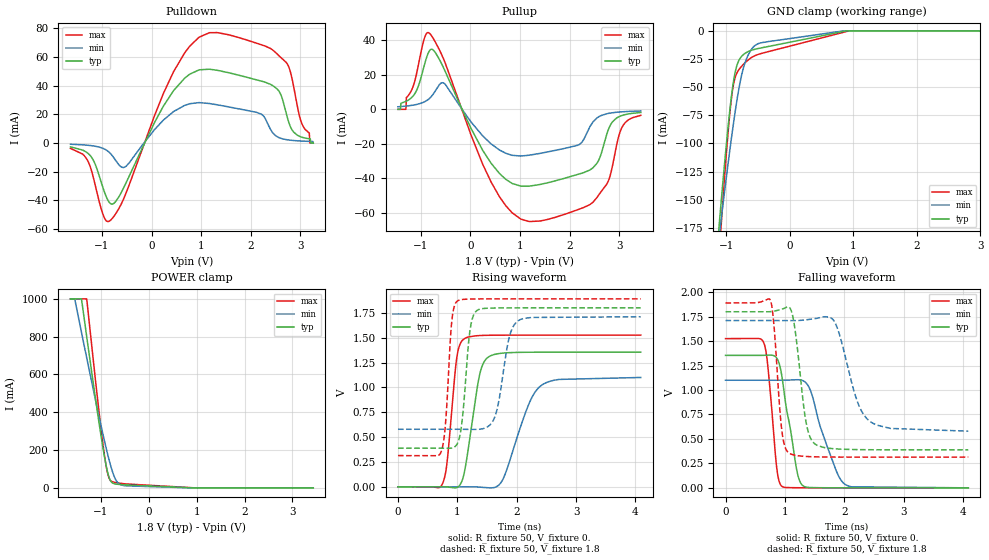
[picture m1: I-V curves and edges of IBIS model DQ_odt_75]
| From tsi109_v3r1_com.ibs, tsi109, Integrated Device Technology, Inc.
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|   MODEL DQ_odt_75
[Model]   DQ_odt_75
Model_type  I/O
Polarity   Non-Inverting
Enable   Active-Low
|   typ   min   max
|C_comp_off 3.363p 3.4p 3.318p
|C_comp_on 3.698p 3.621p 3.948p
C_comp 3.53p 3.51p 3.633p
Cref  =   20pF
Vmeas =   0.9v
Vinl  =   0.650v
Vinh  =   1.150v
[Model Spec]
[Temperature Range]   25   125   0
[Voltage Range] 1.8 1.71 1.89
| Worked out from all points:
|   slope of the pulldown table from 0 to 0.27 V, typ, clamps not added: 15.5 ohm
|   slope of the pullup table from 0 to 0.27 V, typ, clamps not added: 18.7 ohm
|   rising waveform, R_fixture 50, V_fixture 0.: 20-80 % time 205ps typ, 380ps min, 137ps max; typ from 0 V to 1.35 V
|   rising waveform, R_fixture 50, V_fixture 1.8: 20-80 % time 121ps typ, 188ps min, 93.3ps max; typ from 0.389 V to 1.8 V
|   falling waveform, R_fixture 50, V_fixture 0.: 20-80 % time 211ps typ, 348ps min, 129ps max; typ from 1.35 V to 0 V
|   falling waveform, R_fixture 50, V_fixture 1.8: 20-80 % time 164ps typ, 316ps min, 113ps max; typ from 1.8 V to 0.389 V
[Pulldown]
-1.636V   -2.749mA   -869.2uA   -3.779mA
-1.22V    -9.523mA   -1.848mA   -18.31mA
-982.8mV  -30.99mA   -3.738mA   -49.62mA
-834.2mV  -42.14mA   -7.191mA   -54.06mA
-512.5mV  -27.58mA   -16.15mA   -34.67mA
442.9mV   36.55mA    21.94mA    49.75mA
1.166V    51.46mA    27.52mA    76.92mA
2.215V    43.12mA    20.1mA     68.47mA
2.438V    40.09mA    7.284mA    64.95mA
2.715V    20.68mA    2.355mA    56.15mA
3.017V    4.187mA    1.352mA    14.69mA
3.26V     0A         0A         0A
[Pullup]
-1.46V    0A         1.493mA    0A
-1.301V   4.568mA    1.878mA    0A
-1.088V   10.76mA    2.811mA    20.24mA
-826mV    33.9mA     6.297mA    44.13mA
-524mV    23.04mA    14.98mA    28.03mA
416.5mV   -31.17mA   -19.99mA   -42.04mA
1.189V    -44.52mA   -26.57mA   -65.03mA
2.204V    -37.38mA   -20.25mA   -57.75mA
2.476V    -33.78mA   -7.136mA   -53.72mA
2.872V    -7.045mA   -1.945mA   -31.9mA
3.06V     -3.537mA   -1.423mA   -10.29mA
3.436V    -1.832mA   -944.9uA   -3.489mA
[GND Clamp]
-1.636V   -544.5mA   -441.7mA   -680.8mA
-1.123V   -182.1mA   -189mA     -211.5mA
-1.098V   -165.6mA   -177.3mA   -190.4mA
-1.074V   -149.3mA   -165.6mA   -169.7mA
-959.1mV  -80.05mA   -113.8mA   -84.1mA
-914.3mV  -57.55mA   -94.64mA   -59.42mA
-874.4mV  -41.91mA   -78.49mA   -45.25mA
-814.7mV  -28.31mA   -56.62mA   -35.88mA
-720.1mV  -20.78mA   -31.57mA   -29.35mA
-530.9mV  -16.15mA   -12.45mA   -21.7mA
935.2mV   0A         0A         0A
3.26V     0A         0A         0A
[Power Clamp]
-1.636V   1A         1A         1A
-1.546V   1A         997.4mA    1A
-1.407V   998.4mA    824mA      1A
-1.297V   800.3mA    688.1mA    998.9mA
-1.083V   418.1mA    428.5mA    498.6mA
-928.2mV  168.8mA    251.1mA    176.9mA
-848.4mV  71mA       166.8mA    66.16mA
-763.6mV  26.63mA    89.57mA    32.79mA
-648.9mV  18.72mA    27.94mA    26.18mA
-474.4mV  15.54mA    10.87mA    20.84mA
954.8mV   0A         0A         0A
3.436V    0A         0A         0A
[Ramp]
dV/dt_r .812/205.375p .66/380.602p .915/136.332p
dV/dt_f .847/163.938p .679/315.888p .946/112.754p
[Rising Waveform]
R_fixture = 50
V_fixture = 0.
0s        0V         0V         0V
750ps     198.9uV    -789.9nV   31.79mV
820ps     -1.136mV   10.99uV    212.1mV
990ps     -8.18mV    142.4uV    1.294V
1.12ns    152.2mV    239.9uV    1.49V
1.37ns    1.113V     -2.911mV   1.521V
1.53ns    1.308V     -9.701mV   1.524V
1.77ns    1.345V     78.26mV    1.525V
2.41ns    1.354V     1.017V     1.525V
4.09ns    1.354V     1.1V       1.525V
[Rising Waveform]
R_fixture = 50
V_fixture = 1.8
V_fixture_min = 1.71
V_fixture_max = 1.89
0s        388.5mV    578.6mV    314.1mV
730ps     388.1mV    578.7mV    357.9mV
800ps     387.6mV    578.7mV    630.1mV
900ps     389.8mV    578.7mV    1.627V
1ns       434.4mV    578.6mV    1.868V
1.21ns    1.561V     577.2mV    1.888V
1.33ns    1.773V     577.6mV    1.889V
1.63ns    1.798V     701.1mV    1.89V
2.03ns    1.8V       1.672V     1.89V
4.09ns    1.8V       1.71V      1.89V
[Falling Waveform]
R_fixture = 50
V_fixture = 0.
0s        1.354V     1.1V       1.525V
640ps     1.355V     1.1V       1.49V
720ps     1.356V     1.1V       1.203V
860ps     1.329V     1.1V       217.9mV
960ps     1.099V     1.1V       11.48mV
1.2ns     183.3mV    1.105V     1.23mV
1.31ns    19.37mV    1.094V     714.3uV
1.86ns    480.7uV    183.1mV    48.69uV
2.02ns    258.4uV    33.45mV    22.5uV
4.09ns    0V         23.14uV    0V
[Falling Waveform]
R_fixture = 50
V_fixture = 1.8
V_fixture_min = 1.71
V_fixture_max = 1.89
0s        1.8V       1.71V      1.89V
760ps     1.801V     1.71V      1.916V
940ps     1.824V     1.71V      632.1mV
1.08ns    1.84V      1.71V      351.9mV
1.17ns    1.623V     1.71V      333.6mV
1.36ns    662.2mV    1.718V     320.8mV
1.51ns    446.5mV    1.73V      317.2mV
1.84ns    399.2mV    1.694V     314.7mV
2.42ns    389.6mV    685.4mV    314.2mV
4.09ns    388.5mV    579.6mV    314.1mV
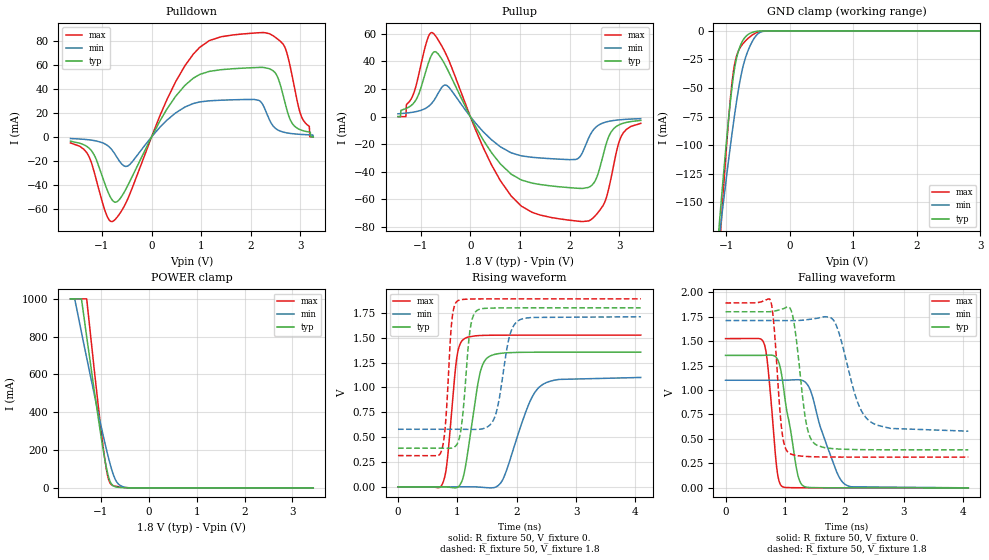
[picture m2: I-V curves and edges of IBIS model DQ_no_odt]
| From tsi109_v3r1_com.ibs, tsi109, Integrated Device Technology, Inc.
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|   MODEL DQ_no_odt
[Model]   DQ_no_odt
Model_type  I/O
Polarity   Non-Inverting
Enable   Active-Low
|   typ   min   max
|C_comp_off 3.919p 3.972p 3.845p
|C_comp_on 3.698p 3.62p 3.948p
C_comp 3.809p 3.796p 3.896p
Cref  =   20pF
Vmeas =   0.9v
Vinl  =   0.650v
Vinh  =   1.150v
[Model Spec]
[Temperature Range]   25   125   0
[Voltage Range] 1.8 1.71 1.89
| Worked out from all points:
|   slope of the pulldown table from 0 to 0.27 V, typ, clamps not added: 13.2 ohm
|   slope of the pullup table from 0 to 0.27 V, typ, clamps not added: 15.4 ohm
|   GND clamp passes 1 mA (typ) near -0.57 V on its own axis
|   POWER clamp passes 1 mA (typ) near -0.54 V on its own axis
|   rising waveform, R_fixture 50, V_fixture 0.: 20-80 % time 205ps typ, 380ps min, 137ps max; typ from 0 V to 1.35 V
|   rising waveform, R_fixture 50, V_fixture 1.8: 20-80 % time 121ps typ, 188ps min, 93.3ps max; typ from 0.389 V to 1.8 V
|   falling waveform, R_fixture 50, V_fixture 0.: 20-80 % time 211ps typ, 348ps min, 129ps max; typ from 1.35 V to 0 V
|   falling waveform, R_fixture 50, V_fixture 1.8: 20-80 % time 164ps typ, 316ps min, 113ps max; typ from 1.8 V to 0.389 V
[Pulldown]
-1.636V   -3.649mA   -1.42mA    -5.055mA
-1.275V   -8.922mA   -2.436mA   -15.46mA
-913.5mV  -42.38mA   -6.562mA   -64.55mA
-784.8mV  -53.15mA   -11.67mA   -70.44mA
-482.8mV  -40.74mA   -24.38mA   -51.92mA
304.3mV   22.85mA    13.69mA    30.62mA
838.9mV   48.83mA    27.75mA    68.81mA
2.235V    57.86mA    27.32mA    86.89mA
2.507V    52.5mA     6.75mA     82.54mA
2.68V     30.08mA    3.705mA    75.24mA
3.002V    5.838mA    2.051mA    19.08mA
3.26V     0A         0A         0A
[Pullup]
-1.46V    0A         2.056mA    0A
-1.301V   5.791mA    2.542mA    0A
-756.7mV  46.08mA    10.65mA    60.6mA
-464.6mV  34.39mA    22.34mA    43.2mA
263.1mV   -17.14mA   -11.08mA   -22.74mA
822.5mV   -41.66mA   -26.22mA   -57.48mA
2.263V    -52.03mA   -25.85mA   -76.01mA
2.496V    -47.78mA   -8.921mA   -72.68mA
2.674V    -28.4mA    -4.593mA   -64.52mA
2.892V    -8.672mA   -2.791mA   -34.76mA
3.085V    -4.751mA   -2.084mA   -11.69mA
3.436V    -2.732mA   -1.461mA   -4.887mA
[GND Clamp]
-1.636V   -543.7mA   -441.2mA   -679.6mA
-1.113V   -173.3mA   -183.3mA   -199.6mA
-1.089V   -157.2mA   -171.9mA   -178.9mA
-1.065V   -141.4mA   -160.5mA   -158.5mA
-948.9mV  -70.59mA   -107.9mA   -69.79mA
-881.1mV  -38.31mA   -79.34mA   -34.33mA
-837.5mV  -24.54mA   -62.52mA   -22.45mA
-784.3mV  -14.23mA   -44.56mA   -15.18mA
-639mV    -2.666mA   -15.21mA   -5.883mA
-532.5mV  -543.1uA   -4.536mA   -1.841mA
-416.4mV  -69.24uA   -425.6uA   -218.8uA
3.26V     0A         0A         0A
[Power Clamp]
-1.636V   1A         1A         1A
-1.549V   1A         1A         1A
-1.411V   1A         828.4mA    1A
-1.298V   800.8mA    688.6mA    1A
-1.047V   355mA      385.4mA    415.3mA
-944.5mV  189.4mA    267.9mA    200.5mA
-857.4mV  74.25mA    174.4mA    62.22mA
-821.5mV  42.19mA    138.8mA    31.99mA
-780.5mV  20.7mA     101.5mA    16.68mA
-657.5mV  3.818mA    26.99mA    6.851mA
-462.8mV  270uA      1.332mA    1.058mA
3.436V    0A         0A         0A
[Ramp]
dV/dt_r .812/205.375p .66/380.602p .915/136.332p
dV/dt_f .847/163.938p .679/315.888p .946/112.754p
[Rising Waveform]
R_fixture = 50
V_fixture = 0.
0s        0V         0V         0V
750ps     198.9uV    -789.9nV   31.79mV
820ps     -1.136mV   10.99uV    212.1mV
990ps     -8.18mV    142.4uV    1.294V
1.12ns    152.2mV    239.9uV    1.49V
1.37ns    1.113V     -2.911mV   1.521V
1.53ns    1.308V     -9.701mV   1.524V
1.77ns    1.345V     78.26mV    1.525V
2.41ns    1.354V     1.017V     1.525V
4.09ns    1.354V     1.1V       1.525V
[Rising Waveform]
R_fixture = 50
V_fixture = 1.8
V_fixture_min = 1.71
V_fixture_max = 1.89
0s        388.5mV    578.6mV    314.1mV
730ps     388.1mV    578.7mV    357.9mV
800ps     387.6mV    578.7mV    630.1mV
900ps     389.8mV    578.7mV    1.627V
1ns       434.4mV    578.6mV    1.868V
1.21ns    1.561V     577.2mV    1.888V
1.33ns    1.773V     577.6mV    1.889V
1.63ns    1.798V     701.1mV    1.89V
2.03ns    1.8V       1.672V     1.89V
4.09ns    1.8V       1.71V      1.89V
[Falling Waveform]
R_fixture = 50
V_fixture = 0.
0s        1.354V     1.1V       1.525V
640ps     1.355V     1.1V       1.49V
720ps     1.356V     1.1V       1.203V
860ps     1.329V     1.1V       217.9mV
960ps     1.099V     1.1V       11.48mV
1.2ns     183.3mV    1.105V     1.23mV
1.31ns    19.37mV    1.094V     714.3uV
1.86ns    480.7uV    183.1mV    48.69uV
2.02ns    258.4uV    33.45mV    22.5uV
4.09ns    0V         23.14uV    0V
[Falling Waveform]
R_fixture = 50
V_fixture = 1.8
V_fixture_min = 1.71
V_fixture_max = 1.89
0s        1.8V       1.71V      1.89V
760ps     1.801V     1.71V      1.916V
940ps     1.824V     1.71V      632.1mV
1.08ns    1.84V      1.71V      351.9mV
1.17ns    1.623V     1.71V      333.6mV
1.36ns    662.2mV    1.718V     320.8mV
1.51ns    446.5mV    1.73V      317.2mV
1.84ns    399.2mV    1.694V     314.7mV
2.42ns    389.6mV    685.4mV    314.2mV
4.09ns    388.5mV    579.6mV    314.1mV
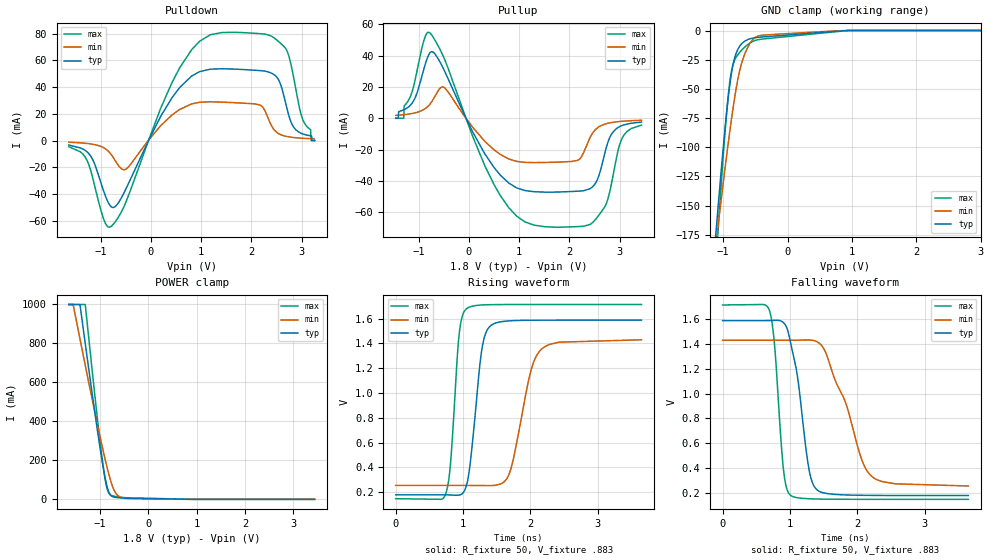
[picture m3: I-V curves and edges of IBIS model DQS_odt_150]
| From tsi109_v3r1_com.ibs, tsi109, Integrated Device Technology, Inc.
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|   MODEL DQS_odt_150
[Model]   DQS_odt_150
Model_type  I/O
Polarity   Non-Inverting
Enable   Active-Low
|   typ   min   max
|C_comp_off 3.705p 3.757p 3.636p
|C_comp_on 3.3p 3.205p 3.514p
C_comp 3.503p 3.481p 3.575p
Cref  =   20pF
Vmeas =   0.9v
Vinl  =   0.650v
Vinh  =   1.150v
[Model Spec]
[Temperature Range]   25   125   0
[Voltage Range] 1.8 1.71 1.89
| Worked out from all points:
|   slope of the pulldown table from 0 to 0.27 V, typ, clamps not added: 14 ohm
|   slope of the pullup table from 0 to 0.27 V, typ, clamps not added: 16.6 ohm
|   rising waveform, R_fixture 50, V_fixture .883: 20-80 % time 155ps typ, 260ps min, 111ps max; typ from 0.179 V to 1.59 V
|   falling waveform, R_fixture 50, V_fixture .883: 20-80 % time 211ps typ, 436ps min, 121ps max; typ from 1.59 V to 0.179 V
[Pulldown]
-1.636V   -3.323mA   -1.212mA   -4.599mA
-1.21V    -11.07mA   -2.446mA   -21.09mA
-933.3mV  -38.78mA   -5.524mA   -59.65mA
-784.8mV  -49.73mA   -10.81mA   -63.97mA
-502.6mV  -36.5mA    -21.48mA   -46.35mA
571.6mV   39.71mA    23.3mA     54.46mA
1.423V    53.79mA    28.81mA    80.93mA
2.176V    52.4mA     26.59mA    80.07mA
2.403V    50.45mA    10.95mA    78.12mA
2.68V     28.57mA    3.287mA    69.15mA
3.002V    5.316mA    1.795mA    18.12mA
3.26V     0A         0A         0A
[Pullup]
-1.46V    0A         1.84mA     0A
-1.301V   5.351mA    2.288mA    0A
-1.078V   12.65mA    3.443mA    23.66mA
-791.3mV  41.1mA     8.484mA    54.75mA
-494.3mV  30.7mA     19.67mA    38.23mA
624.5mV   -36.24mA   -23.04mA   -49.29mA
1.674V    -47.11mA   -28.05mA   -69.43mA
2.204V    -46.44mA   -26.01mA   -69.03mA
2.496V    -42.58mA   -8.056mA   -65.51mA
2.857V    -9.27mA    -2.618mA   -38.81mA
3.06V     -4.507mA   -1.881mA   -12.14mA
3.436V    -2.406mA   -1.258mA   -4.39mA
[GND Clamp]
-1.636V   -544mA     -441.4mA   -680mA
-1.124V   -180.9mA   -188.5mA   -209.5mA
-1.099V   -164.3mA   -176.7mA   -188.1mA
-1.074V   -147.9mA   -165mA     -167.2mA
-964.3mV  -80.44mA   -115.2mA   -82.44mA
-884.7mV  -41.57mA   -81.42mA   -39.48mA
-795.1mV  -19.11mA   -48.76mA   -22.6mA
-660.7mV  -9.028mA   -19.65mA   -14.03mA
-541.2mV  -6.508mA   -7.863mA   -9.392mA
-411.8mV  -5.625mA   -4.125mA   -7.467mA
937.8mV   0A         0A         0A
3.26V     0A         0A         0A
[Power Clamp]
-1.636V   1A         1A         1A
-1.546V   1A         997.3mA    1A
-1.407V   998.2mA    823.6mA    1A
-1.297V   799.4mA    687.6mA    998.5mA
-1.063V   382.4mA    404.2mA    451.3mA
-928mV    166.1mA    250.1mA    171.6mA
-883.1mV  105.4mA    201.6mA    98.24mA
-843.2mV  61.99mA    160.6mA    52.13mA
-758.4mV  18mA       84.13mA    19.98mA
-648.7mV  9.117mA    25.5mA     13.77mA
-474.1mV  6.076mA    5.11mA     8.511mA
3.436V    0A         0A         0A
[Ramp]
dV/dt_r .845/154.678p .705/260.261p .939/110.93p
dV/dt_f .845/210.589p .705/436.081p .939/121.27p
[Rising Waveform]
R_fixture = 50
V_fixture = .883
V_fixture_min = .842
V_fixture_max = .931
0s        179.2mV    255.2mV    148.5mV
740ps     179.2mV    255.2mV    184.6mV
810ps     178.4mV    255.2mV    406.7mV
950ps     178.3mV    255.3mV    1.509V
1.05ns    252.2mV    255.2mV    1.679V
1.27ns    1.317V     254.5mV    1.709V
1.41ns    1.542V     253.8mV    1.712V
1.69ns    1.582V     354.6mV    1.713V
2.15ns    1.587V     1.345V     1.714V
3.65ns    1.588V     1.429V     1.714V
[Falling Waveform]
R_fixture = 50
V_fixture = .883
V_fixture_min = .842
V_fixture_max = .931
0s        1.588V     1.429V     1.714V
700ps     1.588V     1.429V     1.664V
780ps     1.59V      1.429V     1.342V
900ps     1.574V     1.429V     410.3mV
1.02ns    1.385V     1.43V      176.4mV
1.11ns    1.147V     1.43V      161.6mV
1.29ns    371.6mV    1.431V     153mV
1.41ns    221.4mV    1.415V     150.8mV
2.21ns    180.2mV    336.1mV    148.5mV
3.65ns    179.2mV    256.1mV    148.5mV
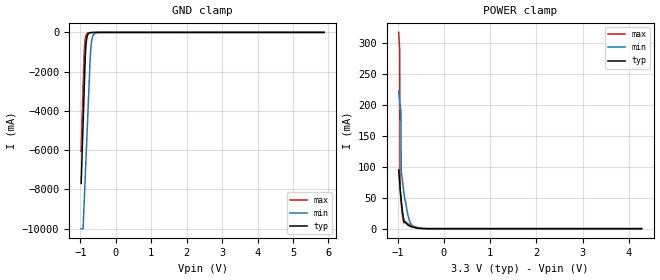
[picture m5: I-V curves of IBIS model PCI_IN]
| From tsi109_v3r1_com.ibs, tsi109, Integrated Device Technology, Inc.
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|   MODEL PCI_IN
[Model]   PCI_IN
Model_type  Input
C_comp 4.536p 4.267p 4.874p
Polarity   Non-Inverting
Enable   Active-High
Vinl =   0.80V
Vinh =   2.00V
[Model Spec]
[Temperature Range]   25.0   125.0   0.0
[Voltage Range] 3.3 3. 3.6
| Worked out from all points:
|   GND clamp passes 1 mA (typ) near -0.58 V on its own axis
|   POWER clamp passes 1 mA (typ) near -0.59 V on its own axis
[GND Clamp]
-976.9mV  -7.694A    -10A       -6.059A
-923.3mV  -4.682A    -10A       -2.776A
-891.1mV  -2.879A    -8.618A    -995.9mA
-863.2mV  -1.353A    -7.407A    -348.1mA
-850.3mV  -868.3mA   -6.848A    -216.4mA
-837.4mV  -553.5mA   -6.29A     -136.9mA
-794.5mV  -126.9mA   -4.431A    -37.38mA
-727.9mV  -18.49mA   -1.562A    -12.3mA
-708.6mV  -11.57mA   -935.5mA   -10.19mA
-670mV    -5.111mA   -330.6mA   -7.318mA
-603.5mV  -1.592mA   -60.06mA   -3.898mA
5.879V    0A         0A         0A
[Power Clamp]
-976.9mV  94.83mA    222.1mA    316.9mA
-955.2mV  74.24mA    206.7mA    290.2mA
-949.7mV  69.36mA    202.9mA    93.51mA
-944.3mV  64.58mA    199.1mA    61.59mA
-928mV    51.03mA    188mA      45.37mA
-922.5mV  46.77mA    94.48mA    40.53mA
-895.3mV  28.34mA    76.94mA    20.86mA
-868.1mV  15.36mA    60.48mA    9.595mA
-840.9mV  10.95mA    45.93mA    9.334mA
-737.6mV  4.25mA     11.82mA    6.323mA
-558.1mV  630.6uA    1.342mA    1.718mA
4.277V    0A         0A         0A
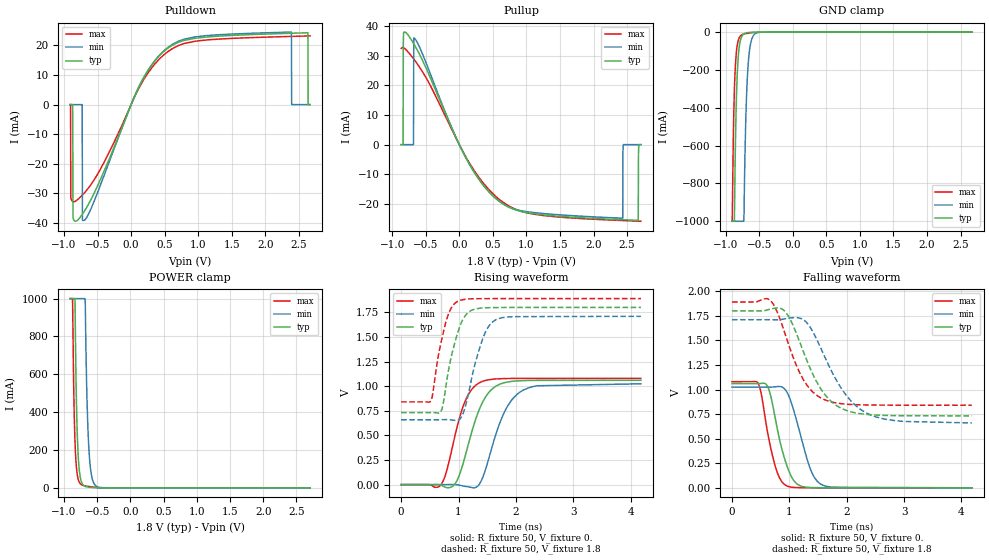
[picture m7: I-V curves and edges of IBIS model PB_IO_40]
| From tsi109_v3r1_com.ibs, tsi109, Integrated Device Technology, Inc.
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|   MODEL PB_IO_40
[Model]   PB_IO_40
Model_type  I/O
Polarity   Non-Inverting
Enable   Active-High
|   typ   min   max
|C_comp_off 3.714p 3.514p 3.979p
|C_comp_on 4.164p 3.795p 4.513p
C_comp 3.939p 3.654p 4.246p
Vinl  =   0.300v
Vinh  =   1.500v
Vmeas =   0.9000V
Cref  =   1.0pF
Rref  =   50.0000
Vref  =   0.0V
[Model Spec]
[Temperature Range]   25   125   0
[Voltage Range] 1.8 1.71 1.89
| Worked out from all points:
|   slope of the pulldown table from 0 to 0.27 V, typ, clamps not added: 22.1 ohm
|   slope of the pullup table from 0 to 0.27 V, typ, clamps not added: 24.6 ohm
|   GND clamp passes 1 mA (typ) near -0.59 V on its own axis
|   POWER clamp passes 1 mA (typ) near -0.54 V on its own axis
|   rising waveform, R_fixture 50, V_fixture 0.: 20-80 % time 351ps typ, 382ps min, 301ps max; typ from 0 V to 1.06 V
|   rising waveform, R_fixture 50, V_fixture 1.8: 20-80 % time 243ps typ, 281ps min, 212ps max; typ from 0.732 V to 1.8 V
|   falling waveform, R_fixture 50, V_fixture 0.: 20-80 % time 258ps typ, 298ps min, 219ps max; typ from 1.06 V to 0 V
|   falling waveform, R_fixture 50, V_fixture 1.8: 20-80 % time 512ps typ, 613ps min, 441ps max; typ from 1.8 V to 0.732 V
[Pulldown]
-906mV    0A         0A         0A
-898.8mV  0A         0A         -31.56mA
-826.6mV  -39.45mA   0A         -32.61mA
-729mV    -37.15mA   0A         -30.65mA
-725.4mV  -37.03mA   -39.06mA   -30.56mA
-696.5mV  -36.04mA   -39.11mA   -29.85mA
611.1mV   20.04mA    20.31mA    18.87mA
2.388V    24.12mA    24.53mA    23.05mA
2.392V    24.12mA    0A         23.05mA
2.634V    24.29mA    0A         23.2mA
2.638V    0A         0A         23.21mA
2.667V    0A         0A         23.23mA
[Pullup]
-866.6mV  0A         0A         32.53mA
-837.7mV  0A         0A         32.8mA
-834.1mV  34.47mA    0A         32.78mA
-816mV    38.07mA    0A         32.53mA
-682.3mV  34.23mA    0A         29.05mA
-675.1mV  33.95mA    36.08mA    28.83mA
740.9mV   -21.2mA    -21.1mA    -20.77mA
2.435V    -25.4mA    -24.88mA   -25.67mA
2.442V    -25.41mA   0A         -25.68mA
2.666V    -25.61mA   0A         -25.88mA
2.674V    0A         0A         -25.88mA
2.706V    0A         0A         -25.91mA
[GND Clamp]
-906mV    -1A        -1A        -1A
-902.1mV  -1A        -1A        -991.7mA
-886.2mV  -1A        -1A        -554.9mA
-870.4mV  -1A        -1A        -309.1mA
-858.5mV  -676.1mA   -1A        -200.9mA
-826.9mV  -218.6mA   -1A        -68.27mA
-771.4mV  -32.66mA   -1A        -17.55mA
-727.9mV  -9.631mA   -986.9mA   -10.26mA
-700.2mV  -5.362mA   -461.4mA   -8.035mA
-664.5mV  -2.969mA   -169.3mA   -5.932mA
-561.6mV  -598.3uA   -9.09mA    -1.877mA
2.667V    0A         0A         0A
[Power Clamp]
-906mV    1A         1A         1A
-872.1mV  1A         1A         1A
-856.7mV  1A         1A         564.2mA
-835.1mV  996.9mA    1A         240.6mA
-819.7mV  566mA      1A         134.1mA
-801.2mV  284.1mA    1A         70.16mA
-748.7mV  43.94mA    1A         19.45mA
-683.9mV  7.977mA    1A         10.28mA
-653.1mV  4.793mA    446.3mA    8.344mA
-628.4mV  3.454mA    219.8mA    7.029mA
-520.4mV  746.2uA    9.952mA    2.56mA
2.706V    0A         0A         0A
[Ramp]
dV/dt_r .636/350.688p .615/382.229p .648/300.4p
dV/dt_f .641/511.996p .631/613.561p .63/441.011p
[Rising Waveform]
R_fixture = 50
V_fixture = 0.
0s        0V         0V         0V
670ps     -1.16mV    -44.07uV   -15.48mV
770ps     -26.04mV   63.45uV    95.18mV
910ps     -11.48mV   804uV      424.1mV
1.14ns    340.9mV    -19.6mV    879mV
1.39ns    801.1mV    30.65mV    1.042V
1.55ns    950.6mV    311.4mV    1.067V
1.77ns    1.031V     698.4mV    1.077V
2.09ns    1.056V     947.3mV    1.079V
4.18ns    1.06V      1.024V     1.08V
[Rising Waveform]
R_fixture = 50
V_fixture = 1.8
V_fixture_min = 1.71
V_fixture_max = 1.89
0s        731.7mV    659.2mV    840.2mV
510ps     732mV      659.2mV    844.1mV
550ps     732.7mV    659.2mV    921.3mV
690ps     737.8mV    659.4mV    1.428V
830ps     1.175V     659.7mV    1.742V
1ns       1.569V     655.4mV    1.866V
1.11ns    1.71V      775.2mV    1.883V
1.43ns    1.795V     1.495V     1.89V
1.65ns    1.799V     1.675V     1.89V
4.18ns    1.8V       1.71V      1.89V
[Falling Waveform]
R_fixture = 50
V_fixture = 0.
0s        1.06V      1.024V     1.08V
440ps     1.06V      1.024V     1.075V
500ps     1.062V     1.024V     984.2mV
600ps     1.05V      1.024V     632.5mV
780ps     630.3mV    1.029V     172.1mV
960ps     220.6mV    971.1mV    18.87mV
1.12ns    46.82mV    698.4mV    2.919mV
1.36ns    3.689mV    201.6mV    683uV
1.56ns    1.25mV     33.8mV     261.3uV
4.18ns    0V         8.143uV    0V
[Falling Waveform]
R_fixture = 50
V_fixture = 1.8
V_fixture_min = 1.71
V_fixture_max = 1.89
0s        1.8V       1.71V      1.89V
640ps     1.813V     1.71V      1.917V
760ps     1.828V     1.709V     1.825V
900ps     1.807V     1.717V     1.611V
1.04ns    1.684V     1.729V     1.37V
1.28ns    1.333V     1.694V     1.068V
1.6ns     963.7mV    1.354V     899.7mV
1.98ns    790.4mV    950.2mV    851.6mV
2.4ns     744.2mV    745.9mV    842.5mV
4.18ns    731.7mV    660.1mV    840.2mV
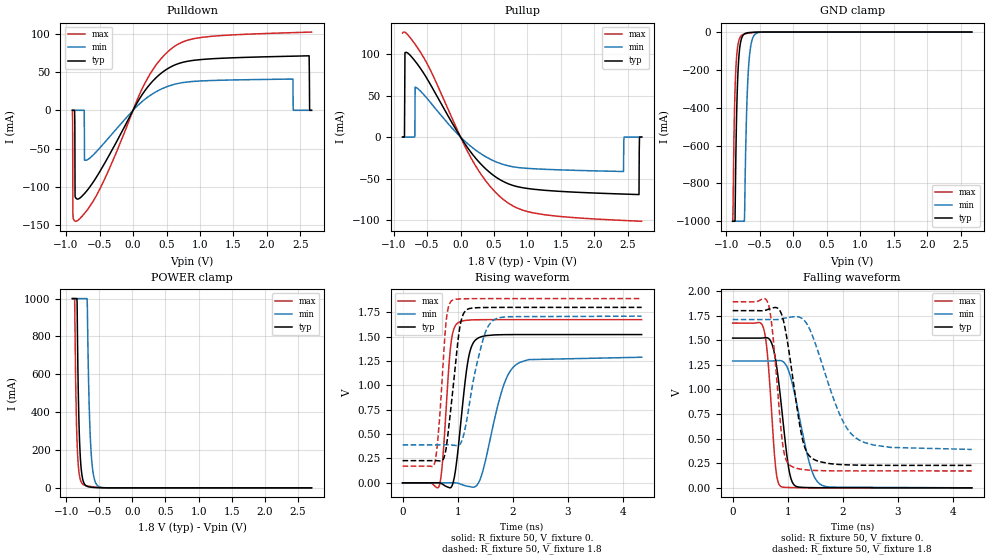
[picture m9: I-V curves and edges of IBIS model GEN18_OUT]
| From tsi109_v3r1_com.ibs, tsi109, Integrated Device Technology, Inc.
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[Model]   GEN18_OUT
Model_type  Output
Polarity   Non-Inverting
Enable   Active-High
|   typ   min   max
|C_comp_off 3.714p 3.514p 3.979p
|C_comp_on 4.671p 4.383p 5.086p
C_comp 4.192p 3.948p 4.532p
Vinl  =   0.300v
Vinh  =   1.500v
Vmeas =   0.9000V
Cref  =   1.0pF
Rref  =   50.0000
Vref  =   0.0V
[Model Spec]
[Temperature Range]   25   125   0
[Voltage Range] 1.8 1.71 1.89
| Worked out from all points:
|   slope of the pulldown table from 0 to 0.27 V, typ, clamps not added: 7.56 ohm
|   slope of the pullup table from 0 to 0.27 V, typ, clamps not added: 9.12 ohm
|   GND clamp passes 1 mA (typ) near -0.59 V on its own axis
|   POWER clamp passes 1 mA (typ) near -0.54 V on its own axis
|   rising waveform, R_fixture 50, V_fixture 0.: 20-80 % time 178ps typ, 338ps min, 120ps max; typ from 0 V to 1.52 V
|   rising waveform, R_fixture 50, V_fixture 1.8: 20-80 % time 179ps typ, 281ps min, 122ps max; typ from 0.228 V to 1.8 V
|   falling waveform, R_fixture 50, V_fixture 0.: 20-80 % time 187ps typ, 296ps min, 125ps max; typ from 1.52 V to 0 V
|   falling waveform, R_fixture 50, V_fixture 1.8: 20-80 % time 255ps typ, 510ps min, 162ps max; typ from 1.8 V to 0.228 V
[Pulldown]
-905.5mV  0A         0A         0A
-901.8mV  0A         0A         -15.16mA
-898.2mV  0A         0A         -134.4mA
-873mV    0A         0A         -144.2mA
-865.7mV  -112.5mA   0A         -144.6mA
-847.7mV  -115.1mA   0A         -144.7mA
-728.5mV  -109mA     0A         -134.9mA
-696mV    -105.6mA   -65mA      -131.3mA
640.2mV   59.77mA    34.43mA    84.61mA
2.63V     71.14mA    0A         102mA
2.637V    0A         0A         102.1mA
2.666V    0A         0A         102.1mA
[Pullup]
-866.2mV  0A         0A         125.4mA
-837.3mV  0A         0A         126.5mA
-830.1mV  101.7mA    0A         126.3mA
-801.2mV  101.8mA    0A         124.4mA
-685.7mV  92.24mA    0A         112.7mA
-674.8mV  91.13mA    60.07mA    111.5mA
672.2mV   -54.92mA   -33.85mA   -77.31mA
2.435V    -68.76mA   -41.53mA   -100.6mA
2.442V    -68.78mA   0A         -100.6mA
2.666V    -69.35mA   0A         -101.4mA
2.673V    0A         0A         -101.4mA
2.705V    0A         0A         -101.6mA
[GND Clamp]
-905.5mV  -1A        -1A        -1A
-901.5mV  -1A        -1A        -974.7mA
-885.7mV  -1A        -1A        -543.1mA
-869.8mV  -997.8mA   -1A        -302.8mA
-858mV    -662.6mA   -1A        -196.7mA
-826.3mV  -214.2mA   -1A        -66.87mA
-770.9mV  -32.02mA   -1A        -17.32mA
-727.3mV  -9.494mA   -973.7mA   -10.21mA
-699.6mV  -5.303mA   -454.7mA   -8.003mA
-664mV    -2.948mA   -166.9mA   -5.905mA
-565.1mV  -634.9uA   -10.08mA   -1.971mA
2.666V    0A         0A         0A
[Power Clamp]
-905.5mV  1A         1A         1A
-871.5mV  1A         1A         999.8mA
-856.1mV  1A         1A         551.7mA
-837.6mV  1A         1A         265.1mA
-816mV    494.2mA    1A         117.5mA
-800.6mV  278.3mA    1A         69.01mA
-742mV    35.25mA    1A         17.64mA
-683.4mV  7.9mA      1A         10.24mA
-652.6mV  4.758mA    440.2mA    8.318mA
-615.6mV  2.935mA    152.1mA    6.395mA
-520mV    740.6uA    9.847mA    2.544mA
2.705V    0A         0A         0A
[Ramp]
dV/dt_r .913/177.771p .773/338.311p 1.004/120.281p
dV/dt_f .943/254.559p .793/510.536p 1.031/161.904p
[Rising Waveform]
R_fixture = 50
V_fixture = 0.
0s        0V         0V         0V
670ps     -91.55uV   -48.8uV    -23.8mV
730ps     -14.39mV   -186.7uV   243.6mV
870ps     -49.24mV   857.7uV    1.386V
1.01ns    355.9mV    -4.331mV   1.644V
1.19ns    1.258V     -35.6mV    1.669V
1.37ns    1.485V     -8.159mV   1.673V
1.81ns    1.52V      956.8mV    1.674V
2.05ns    1.521V     1.208V     1.674V
4.34ns    1.521V     1.288V     1.674V
[Rising Waveform]
R_fixture = 50
V_fixture = 1.8
V_fixture_min = 1.71
V_fixture_max = 1.89
0s        227.8mV    389.2mV    171.6mV
580ps     228.6mV    389.2mV    196.2mV
650ps     226.7mV    389.2mV    504.6mV
790ps     349.2mV    390.3mV    1.652V
890ps     832.8mV    388.3mV    1.868V
1.02ns    1.521V     387.4mV    1.886V
1.1ns     1.727V     473.1mV    1.888V
1.43ns    1.798V     1.406V     1.89V
1.65ns    1.8V       1.668V     1.89V
4.34ns    1.8V       1.71V      1.89V
[Falling Waveform]
R_fixture = 50
V_fixture = 0.
0s        1.521V     1.289V     1.674V
560ps     1.523V     1.289V     1.623V
640ps     1.522V     1.289V     1.302V
780ps     1.299V     1.291V     204.9mV
870ps     906.3mV    1.292V     15.36mV
1ns       260.5mV    1.212V     3.797mV
1.08ns    60.62mV    1.067V     2.372mV
1.4ns     2.408mV    238.9mV    473.4uV
1.6ns     1.072mV    32.47mV    183.1uV
4.34ns    0V         13.39uV    0V
[Falling Waveform]
R_fixture = 50
V_fixture = 1.8
V_fixture_min = 1.71
V_fixture_max = 1.89
0s        1.8V       1.71V      1.89V
640ps     1.813V     1.71V      1.879V
720ps     1.827V     1.709V     1.605V
900ps     1.744V     1.718V     476.5mV
1.04ns    1.319V     1.733V     229.1mV
1.26ns    511.6mV    1.721V     187.4mV
1.46ns    293.4mV    1.528V     177.4mV
1.92ns    238mV      776.1mV    172.3mV
2.24ns    231.1mV    505.4mV    171.8mV
4.34ns    227.8mV    390.2mV    171.6mV
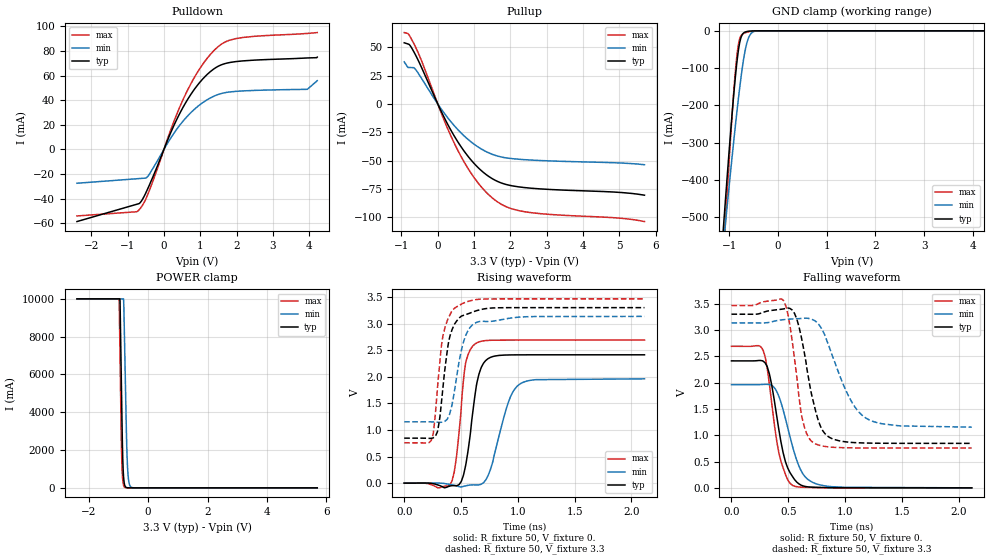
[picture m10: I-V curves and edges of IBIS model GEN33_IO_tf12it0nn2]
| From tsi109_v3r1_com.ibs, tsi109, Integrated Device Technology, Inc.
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|   MODEL GEN33_IO_tf12it0nn2
[Model]   GEN33_IO_tf12it0nn2
Model_type  I/O
C_comp 1.247p 1.176p 1.342p
Polarity   Non-Inverting
Enable   Active-High
|   typ   min   max
Vinl   =   0.800v
Vinh   =   2.000v
Vmeas  =   1.65V
[Model Spec]
[Temperature Range]   25   125   0
[Voltage Range] 3.3 3.135 3.465
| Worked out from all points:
|   slope of the pulldown table from 0 to 0.495 V, typ, clamps not added: 15.2 ohm
|   slope of the pullup table from 0 to 0.495 V, typ, clamps not added: 16.3 ohm
|   GND clamp passes 1 mA (typ) near -0.60 V on its own axis
|   POWER clamp passes 1 mA (typ) near -0.62 V on its own axis
|   rising waveform, R_fixture 50, V_fixture 0.: 20-80 % time 92.1ps typ, 147ps min, 70.9ps max; typ from 0 V to 2.41 V
|   rising waveform, R_fixture 50, V_fixture 3.3: 20-80 % time 90.2ps typ, 107ps min, 84.6ps max; typ from 0.845 V to 3.3 V
|   falling waveform, R_fixture 50, V_fixture 0.: 20-80 % time 121ps typ, 155ps min, 109ps max; typ from 2.41 V to 0 V
|   falling waveform, R_fixture 50, V_fixture 3.3: 20-80 % time 137ps typ, 233ps min, 99.2ps max; typ from 3.3 V to 0.845 V
[Pulldown]
-2.396V   -58.62mA   -27.49mA   -54.06mA
-756mV    -44.63mA   -23.86mA   -50.65mA
-662.3mV  -43.5mA    -23.65mA   -48.32mA
-434.7mV  -31.22mA   -21.51mA   -35.84mA
187.8mV   13.66mA    9.223mA    15.92mA
555.9mV   35.75mA    23.97mA    42.3mA
1.071V    57.29mA    38.05mA    69.29mA
1.52V     67.92mA    44.88mA    84.11mA
1.821V    70.64mA    46.71mA    88.84mA
2.169V    71.91mA    47.53mA    90.92mA
3.95V     74.3mA     48.8mA     94.22mA
4.224V    74.99mA    55.83mA    94.92mA
[Pullup]
-924.1mV  53.85mA    37.04mA    62.83mA
-796.9mV  52.53mA    32.1mA     61.01mA
-663mV    46.15mA    31.85mA    53.38mA
-576mV    40.84mA    28.84mA    47.65mA
133.5mV   -9.109mA   -6.162mA   -11.06mA
588.7mV   -35.17mA   -23.83mA   -43.1mA
1.037V    -53.69mA   -36.34mA   -66.5mA
1.526V    -66.31mA   -44.68mA   -83.43mA
1.874V    -70.9mA    -47.5mA    -90.41mA
2.383V    -73.68mA   -49.1mA    -94.93mA
5.067V    -78.08mA   -52.1mA    -100.8mA
5.696V    -80.41mA   -53.59mA   -103.6mA
[GND Clamp]
-2.396V   -2.986A    -2.401A    -3.708A
-1.121V   -533.1mA   -577.5mA   -612.5mA
-1.081V   -461.9mA   -523.7mA   -523.1mA
-937.9mV  -219.3mA   -335.6mA   -221.8mA
-890.1mV  -147.5mA   -275.8mA   -136.1mA
-850.3mV  -94.66mA   -227.6mA   -77.18mA
-786.5mV  -33.49mA   -155.3mA   -22.37mA
-746.7mV  -14.38mA   -114.5mA   -11.27mA
-690.9mV  -4.535mA   -65.97mA   -6.169mA
-587.4mV  -835.4uA   -14.53mA   -2.198mA
-443.9mV  -45.4uA    -524.9uA   -178.2uA
4.224V    0A         0A         0A
[Power Clamp]
-2.396V   10A        10A        10A
-976.4mV  10A        10A        10A
-952.8mV  10A        10A        7.72A
-944.9mV  9.88A      10A        6.899A
-905.5mV  6.038A     10A        2.817A
-881.8mV  3.741A     10A        1.213A
-858.1mV  1.8A       10A        482.2mA
-826.6mV  591.4mA    10A        135.5mA
-787.2mV  135.4mA    7.258A     30.19mA
-700.4mV  6.514mA    1.351A     4.157mA
-574.2mV  501.8uA    37.92mA    1.305mA
5.696V    0A         0A         0A
[Ramp]
dV/dt_r 1.448/92.129p 1.177/146.688p 1.614/70.788p
dV/dt_f 1.473/136.637p 1.19/233.06p 1.625/99.24p
[Rising Waveform]
R_fixture = 50
V_fixture = 0.
0s        514.3nV    829.9nV    0V
315ps     -47.89mV   -434.8uV   -89.09mV
420ps     -48.36mV   -33.69mV   35.24mV
460ps     -48.53mV   -53.68mV   490.4mV
540ps     324.4mV    -51.57mV   2.25V
640ps     1.887V     -34.35mV   2.639V
740ps     2.343V     150.7mV    2.684V
915ps     2.41V      1.509V     2.689V
1.015ns   2.412V     1.858V     2.689V
2.115ns   2.413V     1.961V     2.689V
[Rising Waveform]
R_fixture = 50
V_fixture = 3.3
V_fixture_min = 3.135
V_fixture_max = 3.465
0s        845.1mV    1.152V     757.2mV
235ps     841.3mV    1.152V     794.1mV
260ps     857.8mV    1.15V      998.3mV
290ps     953.2mV    1.146V     1.714V
345ps     1.882V     1.152V     2.807V
400ps     2.742V     1.299V     3.152V
465ps     3.058V     2.044V     3.32V
540ps     3.168V     2.769V     3.402V
655ps     3.253V     3.035V     3.456V
2.115ns   3.3V       3.135V     3.465V
[Falling Waveform]
R_fixture = 50
V_fixture = 0.
0s        2.413V     1.961V     2.69V
280ps     2.405V     1.965V     2.608V
335ps     2.157V     1.962V     1.951V
380ps     1.623V     1.895V     1.168V
420ps     1.072V     1.722V     639.2mV
475ps     498.9mV    1.318V     256.4mV
540ps     206.9mV    770.5mV    44.37mV
645ps     29.04mV    219.5mV    10.6mV
790ps     7.195mV    50.93mV    2.931mV
2.115ns   27.36uV    31.28uV    31.61uV
[Falling Waveform]
R_fixture = 50
V_fixture = 3.3
V_fixture_min = 3.135
V_fixture_max = 3.465
0s        3.3V       3.135V     3.465V
460ps     3.401V     3.196V     3.555V
515ps     3.409V     3.206V     3.079V
575ps     3.209V     3.214V     2.116V
620ps     2.81V      3.219V     1.343V
720ps     1.644V     3.191V     859.4mV
845ps     985.4mV    2.766V     780.4mV
1.025ns   869.6mV    1.77V      761.2mV
1.185ns   851.7mV    1.324V     758.1mV
2.115ns   845.2mV    1.153V     757.3mV
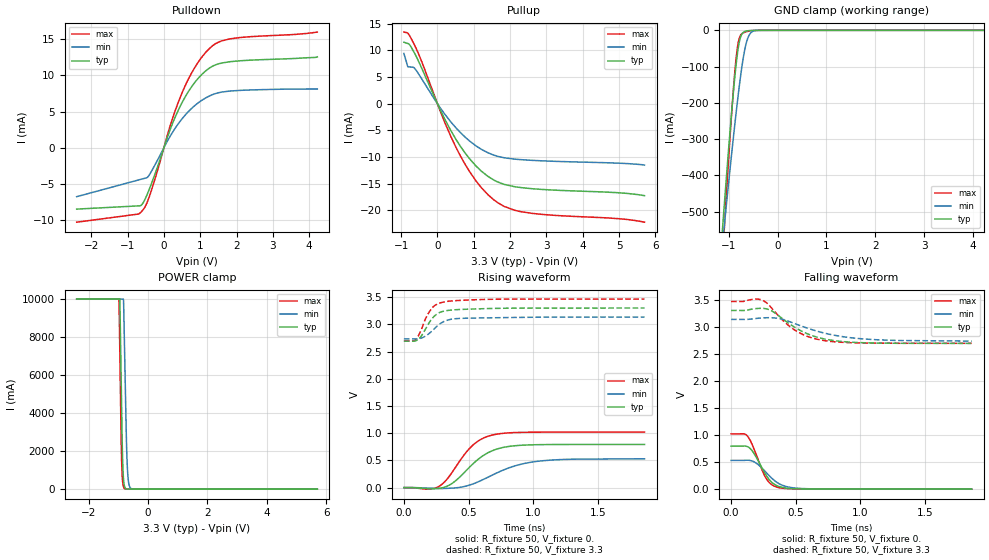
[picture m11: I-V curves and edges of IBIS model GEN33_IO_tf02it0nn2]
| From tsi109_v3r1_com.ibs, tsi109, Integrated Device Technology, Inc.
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|   MODEL GEN33_IO_tf02it0nn2
[Model]   GEN33_IO_tf02it0nn2
Model_type  I/O
C_comp 1.184p 1.112p 1.271p
Polarity   Non-Inverting
Enable   Active-High
|   typ   min   max
Vinl   =   0.800v
Vinh   =   2.000v
Vmeas  =   1.65V
[Model Spec]
[Temperature Range]   25   125   0
[Voltage Range] 3.3 3.135 3.465
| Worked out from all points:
|   slope of the pulldown table from 0 to 0.495 V, typ, clamps not added: 80 ohm
|   slope of the pullup table from 0 to 0.495 V, typ, clamps not added: 76 ohm
|   GND clamp passes 1 mA (typ) near -0.60 V on its own axis
|   POWER clamp passes 1 mA (typ) near -0.62 V on its own axis
|   rising waveform, R_fixture 50, V_fixture 0.: 20-80 % time 230ps typ, 323ps min, 202ps max; typ from 0 V to 0.794 V
|   rising waveform, R_fixture 50, V_fixture 3.3: 20-80 % time 107ps typ, 127ps min, 97.8ps max; typ from 2.69 V to 3.3 V
|   falling waveform, R_fixture 50, V_fixture 0.: 20-80 % time 118ps typ, 144ps min, 106ps max; typ from 0.794 V to 0 V
|   falling waveform, R_fixture 50, V_fixture 3.3: 20-80 % time 275ps typ, 373ps min, 237ps max; typ from 3.3 V to 2.69 V
[Pulldown]
-2.4V     -8.474mA   -6.758mA   -10.28mA
-705.4mV  -8.028mA   -4.456mA   -9.161mA
-564.7mV  -7.544mA   -4.265mA   -8.519mA
-397.3mV  -5.675mA   -3.724mA   -6.694mA
-176.3mV  -2.658mA   -1.719mA   -3.165mA
192.1mV   2.763mA    1.758mA    3.33mA
480.2mV   6.041mA    3.873mA    7.342mA
882mV     9.223mA    5.958mA    11.34mA
1.13V     10.53mA    6.827mA    13.06mA
1.331V    11.25mA    7.327mA    14.06mA
1.82V     11.9mA     7.841mA    15.05mA
4.224V    12.56mA    8.123mA    15.99mA
[Pullup]
-924.4mV  11.54mA    9.439mA    13.44mA
-817.2mV  11.3mA     6.948mA    13.24mA
-663.2mV  9.892mA    6.827mA    11.44mA
-576.1mV  8.753mA    6.18mA     10.21mA
194.2mV   -2.791mA   -1.888mA   -3.393mA
636.3mV   -8.028mA   -5.438mA   -9.847mA
1.065V    -11.7mA    -7.919mA   -14.51mA
1.554V    -14.32mA   -9.642mA   -18.03mA
2.123V    -15.55mA   -10.38mA   -19.97mA
2.612V    -15.94mA   -10.62mA   -20.56mA
4.977V    -16.69mA   -11.14mA   -21.54mA
5.7V      -17.24mA   -11.51mA   -22.21mA
[GND Clamp]
-2.4V     -2.994A    -2.407A    -3.719A
-1.124V   -538mA     -581.2mA   -618.7mA
-1.092V   -480.9mA   -538mA     -546.9mA
-1.068V   -438.5mA   -505.9mA   -493.7mA
-932.5mV  -210.8mA   -328.7mA   -211.5mA
-852.8mV  -97.7mA    -230.6mA   -80.32mA
-788.9mV  -35.11mA   -157.9mA   -23.45mA
-741.1mV  -12.71mA   -109.1mA   -10.44mA
-685.3mV  -4.075mA   -61.77mA   -5.86mA
-581.6mV  -759.7uA   -13.1mA    -2.046mA
-438mV    -39.16uA   -446.5uA   -155.4uA
4.224V    0A         0A         0A
[Power Clamp]
-2.4V     10A        10A        10A
-979mV    10A        10A        10A
-947.4mV  10A        10A        7.164A
-908mV    6.281A     10A        3.058A
-884.3mV  3.983A     10A        1.332A
-852.7mV  1.498A     10A        387.8mA
-821.1mV  483.4mA    9.885A     109mA
-789.5mV  148.4mA    7.442A     32.83mA
-702.7mV  6.966mA    1.436A     4.27mA
-655.3mV  2.051mA    388.6mA    2.727mA
-576.4mV  519.3uA    40.48mA    1.336mA
5.7V      0A         0A         0A
[Ramp]
dV/dt_r .476/230.063p .318/323.059p .612/201.762p
dV/dt_f .365/274.969p .241/374.442p .463/237.433p
[Rising Waveform]
R_fixture = 50
V_fixture = 0.
0s        0V         0V         0V
185ps     -20.24mV   -8.288mV   -28.27mV
280ps     -9.948mV   -16.97mV   35.78mV
375ps     81.29mV    -8.553mV   288.1mV
520ps     405.4mV    56.43mV    750.9mV
600ps     567.4mV    134.5mV    892.9mV
680ps     674.4mV    226.6mV    964.2mV
865ps     771.2mV    404.2mV    1.012V
1.065ns   790.1mV    492.3mV    1.019V
1.86ns    793.7mV    530.4mV    1.02V
[Rising Waveform]
R_fixture = 50
V_fixture = 3.3
V_fixture_min = 3.135
V_fixture_max = 3.465
0s        2.691V     2.733V     2.693V
90ps      2.696V     2.731V     2.719V
130ps     2.771V     2.745V     2.879V
165ps     2.904V     2.782V     3.093V
220ps     3.112V     2.884V     3.306V
275ps     3.217V     3.003V     3.389V
320ps     3.248V     3.063V     3.416V
385ps     3.266V     3.101V     3.433V
505ps     3.28V      3.114V     3.448V
1.86ns    3.3V       3.135V     3.465V
[Falling Waveform]
R_fixture = 50
V_fixture = 0.
0s        793.7mV    530.7mV    1.02V
125ps     786.7mV    534mV      983.8mV
175ps     667.7mV    508.2mV    753.1mV
235ps     410.5mV    397.6mV    379.8mV
275ps     241.2mV    298.2mV    183.1mV
315ps     125.8mV    201.9mV    81.41mV
360ps     58.96mV    116.5mV    33.3mV
450ps     14.43mV    36.11mV    8.764mV
575ps     4.444mV    9.419mV    3.204mV
1.86ns    2.98uV     32.28uV    1.306uV
[Falling Waveform]
R_fixture = 50
V_fixture = 3.3
V_fixture_min = 3.135
V_fixture_max = 3.465
0s        3.3V       3.135V     3.465V
235ps     3.339V     3.161V     3.494V
310ps     3.298V     3.166V     3.353V
395ps     3.152V     3.139V     3.13V
480ps     3.008V     3.069V     2.958V
575ps     2.884V     2.985V     2.835V
695ps     2.788V     2.898V     2.754V
850ps     2.728V     2.821V     2.713V
1.05ns    2.702V     2.769V     2.698V
1.86ns    2.692V     2.734V     2.693V
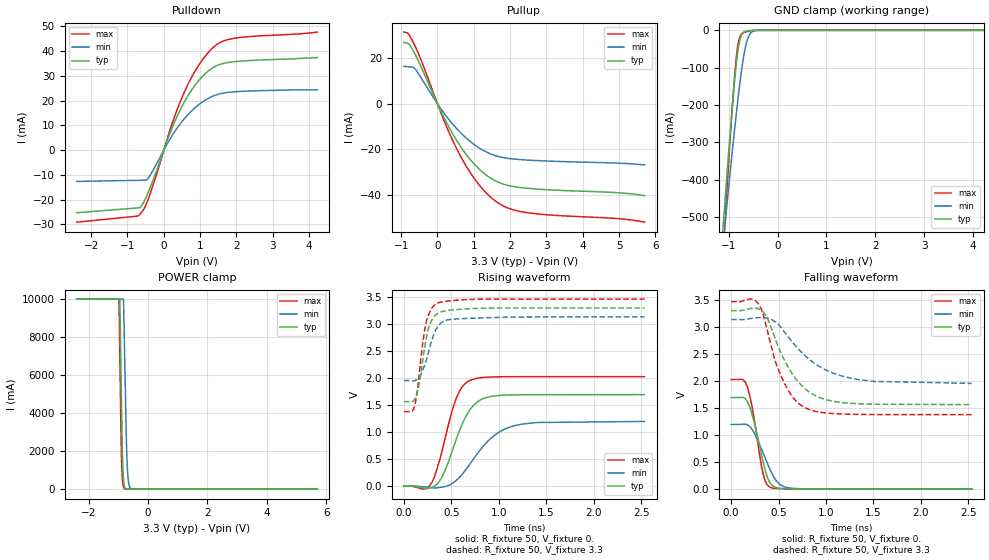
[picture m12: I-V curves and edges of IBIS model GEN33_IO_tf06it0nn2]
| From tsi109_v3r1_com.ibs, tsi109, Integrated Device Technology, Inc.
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|   MODEL GEN33_IO_tf06it0nn2
[Model]   GEN33_IO_tf06it0nn2
Model_type  I/O
C_comp 1.25p 1.174p 1.348p
Polarity   Non-Inverting
Enable   Active-High
|   typ   min   max
Vinl   =   0.800v
Vinh   =   2.000v
Vmeas  =   1.65V
[Model Spec]
[Temperature Range]   25   125   0
[Voltage Range] 3.3 3.135 3.465
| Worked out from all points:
|   slope of the pulldown table from 0 to 0.495 V, typ, clamps not added: 28.2 ohm
|   slope of the pullup table from 0 to 0.495 V, typ, clamps not added: 32.6 ohm
|   GND clamp passes 1 mA (typ) near -0.60 V on its own axis
|   POWER clamp passes 1 mA (typ) near -0.62 V on its own axis
|   rising waveform, R_fixture 50, V_fixture 0.: 20-80 % time 229ps typ, 345ps min, 188ps max; typ from 0 V to 1.69 V
|   rising waveform, R_fixture 50, V_fixture 3.3: 20-80 % time 103ps typ, 130ps min, 93.2ps max; typ from 1.56 V to 3.3 V
|   falling waveform, R_fixture 50, V_fixture 0.: 20-80 % time 136ps typ, 179ps min, 113ps max; typ from 1.69 V to 0 V
|   falling waveform, R_fixture 50, V_fixture 3.3: 20-80 % time 317ps typ, 447ps min, 247ps max; typ from 3.3 V to 1.56 V
[Pulldown]
-2.399V   -25.3mA    -12.63mA   -29.11mA
-731.1mV  -23.35mA   -12.19mA   -26.68mA
-610.6mV  -22.46mA   -12.16mA   -25.09mA
-423.1mV  -16.79mA   -11.23mA   -19.56mA
213.1mV   8.483mA    5.538mA    10.08mA
561.3mV   19.4mA     12.68mA    23.35mA
963.1mV   28.18mA    18.43mA    34.41mA
1.231V    32.1mA     21mA       39.62mA
1.432V    34.02mA    22.32mA    42.42mA
1.68V     35.2mA     23.2mA     44.34mA
2.108V    36mA       23.77mA    45.58mA
4.224V    37.46mA    24.37mA    47.74mA
[Pullup]
-924.3mV  26.91mA    16.42mA    31.38mA
-797mV    26.27mA    16.19mA    30.51mA
-663.1mV  23.08mA    15.93mA    26.69mA
-576.1mV  20.42mA    14.42mA    23.83mA
120.4mV   -4.121mA   -2.788mA   -5.005mA
595.8mV   -17.76mA   -12.03mA   -21.76mA
1.018V    -26.51mA   -17.95mA   -32.82mA
1.507V    -32.98mA   -22.23mA   -41.46mA
1.955V    -35.77mA   -23.93mA   -45.75mA
2.484V    -37.01mA   -24.66mA   -47.71mA
4.888V    -38.85mA   -25.93mA   -50.16mA
5.699V    -40.21mA   -26.77mA   -51.83mA
[GND Clamp]
-2.399V   -2.991A    -2.405A    -3.715A
-1.115V   -521.9mA   -569mA     -598.4mA
-1.091V   -479.1mA   -536.7mA   -544.7mA
-1.067V   -436.8mA   -504.6mA   -491.6mA
-939.6mV  -221.9mA   -337.7mA   -224.9mA
-851.9mV  -96.6mA    -229.5mA   -79.2mA
-788.1mV  -34.55mA   -157mA     -23.09mA
-748.2mV  -14.84mA   -115.9mA   -11.48mA
-692.4mV  -4.638mA   -67.08mA   -6.25mA
-588.8mV  -857uA     -14.92mA   -2.236mA
-445.3mV  -46.64uA   -542.7uA   -183.5uA
4.224V    0A         0A         0A
[Power Clamp]
-2.399V   10A        10A        10A
-978.1mV  10A        10A        10A
-946.5mV  10A        10A        7.069A
-907.1mV  6.193A     10A        2.969A
-883.4mV  3.895A     10A        1.288A
-851.8mV  1.453A     10A        374.2mA
-820.3mV  468mA      9.817A     105.4mA
-788.7mV  143.5mA    7.375A     31.7mA
-701.9mV  6.728mA    1.404A     4.234mA
-654.5mV  2.014mA    379.7mA    2.707mA
-575.6mV  512.8uA    39.56mA    1.324mA
5.699V    0A         0A         0A
[Ramp]
dV/dt_r 1.015/228.756p .717/344.077p 1.216/188.269p
dV/dt_f 1.043/317.591p .709/447.763p 1.253/247.491p
[Rising Waveform]
R_fixture = 50
V_fixture = 0.
0s        714nV      0V         719.3nV
210ps     -43.01mV   -16.83mV   -59.52mV
285ps     -33.8mV    -32.41mV   36.83mV
395ps     146.5mV    -24.9mV    597.9mV
545ps     831.3mV    91.18mV    1.59V
620ps     1.169V     228.1mV    1.848V
700ps     1.422V     416.9mV    1.958V
915ps     1.658V     879.5mV    2.019V
1.155ns   1.688V     1.111V     2.025V
2.535ns   1.692V     1.195V     2.026V
[Rising Waveform]
R_fixture = 50
V_fixture = 3.3
V_fixture_min = 3.135
V_fixture_max = 3.465
0s        1.562V     1.954V     1.377V
110ps     1.596V     1.949V     1.463V
140ps     1.738V     1.977V     1.745V
165ps     1.94V      2.03V      2.134V
195ps     2.287V     2.132V     2.605V
230ps     2.679V     2.3V       2.999V
275ps     3.006V     2.581V     3.234V
350ps     3.192V     2.934V     3.387V
575ps     3.272V     3.099V     3.446V
2.535ns   3.3V       3.135V     3.465V
[Falling Waveform]
R_fixture = 50
V_fixture = 0.
0s        1.692V     1.195V     2.026V
120ps     1.695V     1.199V     2.025V
170ps     1.621V     1.19V      1.896V
220ps     1.381V     1.106V     1.531V
335ps     521.7mV    677.5mV    297mV
375ps     257mV      507.7mV    97.18mV
415ps     106.6mV    346.4mV    32.96mV
510ps     16.11mV    92.43mV    9.22mV
650ps     5.688mV    15.43mV    3.899mV
2.535ns   12.24uV    11.96uV    22.76uV
[Falling Waveform]
R_fixture = 50
V_fixture = 3.3
V_fixture_min = 3.135
V_fixture_max = 3.465
0s        3.3V       3.135V     3.465V
295ps     3.327V     3.171V     3.402V
380ps     3.168V     3.161V     2.939V
470ps     2.756V     3.087V     2.344V
545ps     2.444V     2.944V     2.02V
660ps     2.091V     2.686V     1.677V
785ps     1.847V     2.458V     1.5V
1.03ns    1.64V      2.175V     1.403V
1.35ns    1.578V     2.023V     1.382V
2.535ns   1.562V     1.955V     1.377V
